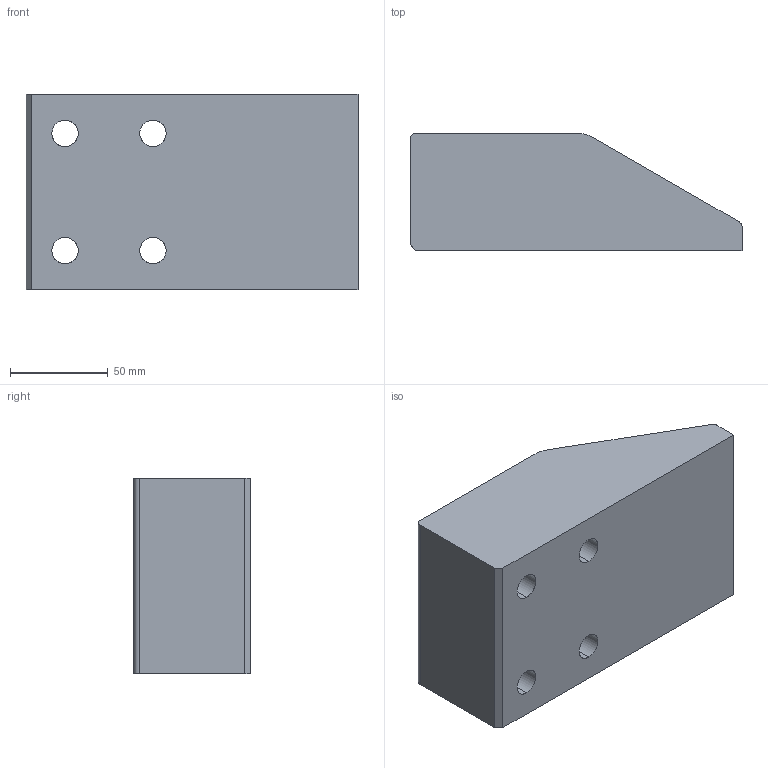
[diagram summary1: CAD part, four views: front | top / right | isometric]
IGES file: header records copied from the file, then geometry measured from it (millimetres).
Start section: START RECORD GO HERE.
Global section: file name: A935-10017060.igs; native system: DASSAULT SYSTEMES CATIA V5 R20 - www.3ds.com; preprocessor: CATIA Version 5 Release 20 ; author: Utente; organization: NB04-ASUS; date: 20200417.104107; units: millimetre
Bounding box: 170 x 60 x 100 mm (x, y, z)
Surface area: 71353.7 mm2 (no closed solid volume)
Topology: 0 solids, 0 shells, 39 faces, 182 edges, 182 vertices
Faces by surface type: revolution 27, extrusion 12
